VERSION 5.7 ;
  NOWIREEXTENSIONATPIN ON ;
  DIVIDERCHAR "/" ;
  BUSBITCHARS "[]" ;
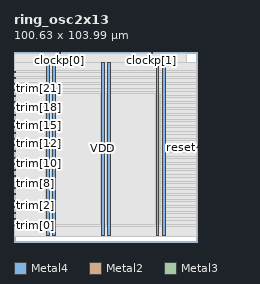
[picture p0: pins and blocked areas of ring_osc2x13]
MACRO ring_osc2x13
  CLASS BLOCK ;
  FOREIGN ring_osc2x13 ;
  ORIGIN 0.000 0.000 ;
  SIZE 100.630 BY 103.990 ;
  PIN VDD
    DIRECTION INOUT ;
    USE POWER ;
    PORT
      LAYER Metal4 ;
        RECT 17.760 3.620 19.360 98.300 ;
    END
    PORT
      LAYER Metal4 ;
        RECT 47.760 3.620 49.360 98.300 ;
    END
    PORT
      LAYER Metal4 ;
        RECT 77.760 3.620 79.360 98.300 ;
    END
  END VDD
  PIN VSS
    DIRECTION INOUT ;
    USE GROUND ;
    PORT
      LAYER Metal4 ;
        RECT 21.060 3.620 22.660 98.300 ;
    END
    PORT
      LAYER Metal4 ;
        RECT 51.060 3.620 52.660 98.300 ;
    END
    PORT
      LAYER Metal4 ;
        RECT 81.060 3.620 82.660 98.300 ;
    END
  END VSS
  PIN clockp[0]
    DIRECTION OUTPUT ;
    USE SIGNAL ;
    ANTENNADIFFAREA 4.024000 ;
    PORT
      LAYER Metal2 ;
        RECT 24.640 103.430 25.200 103.990 ;
    END
  END clockp[0]
  PIN clockp[1]
    DIRECTION OUTPUT ;
    USE SIGNAL ;
    ANTENNADIFFAREA 4.024000 ;
    PORT
      LAYER Metal2 ;
        RECT 75.040 103.430 75.600 103.990 ;
    END
  END clockp[1]
  PIN reset
    DIRECTION INPUT ;
    USE SIGNAL ;
    ANTENNAGATEAREA 3.848000 ;
    ANTENNADIFFAREA 1.231200 ;
    PORT
      LAYER Metal3 ;
        RECT 100.070 51.520 100.630 52.080 ;
    END
  END reset
  PIN trim[0]
    DIRECTION INPUT ;
    USE SIGNAL ;
    ANTENNAGATEAREA 0.552000 ;
    ANTENNADIFFAREA 0.410400 ;
    PORT
      LAYER Metal3 ;
        RECT 0.000 8.960 0.560 9.520 ;
    END
  END trim[0]
  PIN trim[10]
    DIRECTION INPUT ;
    USE SIGNAL ;
    ANTENNAGATEAREA 0.552000 ;
    ANTENNADIFFAREA 0.410400 ;
    PORT
      LAYER Metal3 ;
        RECT 0.000 42.560 0.560 43.120 ;
    END
  END trim[10]
  PIN trim[11]
    DIRECTION INPUT ;
    USE SIGNAL ;
    ANTENNAGATEAREA 0.552000 ;
    ANTENNADIFFAREA 0.410400 ;
    PORT
      LAYER Metal3 ;
        RECT 0.000 45.920 0.560 46.480 ;
    END
  END trim[11]
  PIN trim[12]
    DIRECTION INPUT ;
    USE SIGNAL ;
    ANTENNAGATEAREA 0.552000 ;
    ANTENNADIFFAREA 0.410400 ;
    PORT
      LAYER Metal3 ;
        RECT 0.000 49.280 0.560 49.840 ;
    END
  END trim[12]
  PIN trim[13]
    DIRECTION INPUT ;
    USE SIGNAL ;
    ANTENNAGATEAREA 0.552000 ;
    ANTENNADIFFAREA 0.410400 ;
    PORT
      LAYER Metal3 ;
        RECT 0.000 52.640 0.560 53.200 ;
    END
  END trim[13]
  PIN trim[14]
    DIRECTION INPUT ;
    USE SIGNAL ;
    ANTENNAGATEAREA 0.552000 ;
    ANTENNADIFFAREA 0.410400 ;
    PORT
      LAYER Metal3 ;
        RECT 0.000 56.000 0.560 56.560 ;
    END
  END trim[14]
  PIN trim[15]
    DIRECTION INPUT ;
    USE SIGNAL ;
    ANTENNAGATEAREA 0.552000 ;
    ANTENNADIFFAREA 0.410400 ;
    PORT
      LAYER Metal3 ;
        RECT 0.000 59.360 0.560 59.920 ;
    END
  END trim[15]
  PIN trim[16]
    DIRECTION INPUT ;
    USE SIGNAL ;
    ANTENNAGATEAREA 0.552000 ;
    ANTENNADIFFAREA 0.410400 ;
    PORT
      LAYER Metal3 ;
        RECT 0.000 62.720 0.560 63.280 ;
    END
  END trim[16]
  PIN trim[17]
    DIRECTION INPUT ;
    USE SIGNAL ;
    ANTENNAGATEAREA 0.552000 ;
    ANTENNADIFFAREA 0.410400 ;
    PORT
      LAYER Metal3 ;
        RECT 0.000 66.080 0.560 66.640 ;
    END
  END trim[17]
  PIN trim[18]
    DIRECTION INPUT ;
    USE SIGNAL ;
    ANTENNAGATEAREA 0.552000 ;
    ANTENNADIFFAREA 0.410400 ;
    PORT
      LAYER Metal3 ;
        RECT 0.000 69.440 0.560 70.000 ;
    END
  END trim[18]
  PIN trim[19]
    DIRECTION INPUT ;
    USE SIGNAL ;
    ANTENNAGATEAREA 0.552000 ;
    ANTENNADIFFAREA 0.410400 ;
    PORT
      LAYER Metal3 ;
        RECT 0.000 72.800 0.560 73.360 ;
    END
  END trim[19]
  PIN trim[1]
    DIRECTION INPUT ;
    USE SIGNAL ;
    ANTENNAGATEAREA 0.552000 ;
    ANTENNADIFFAREA 0.410400 ;
    PORT
      LAYER Metal3 ;
        RECT 0.000 12.320 0.560 12.880 ;
    END
  END trim[1]
  PIN trim[20]
    DIRECTION INPUT ;
    USE SIGNAL ;
    ANTENNAGATEAREA 0.552000 ;
    ANTENNADIFFAREA 0.410400 ;
    PORT
      LAYER Metal3 ;
        RECT 0.000 76.160 0.560 76.720 ;
    END
  END trim[20]
  PIN trim[21]
    DIRECTION INPUT ;
    USE SIGNAL ;
    ANTENNAGATEAREA 0.552000 ;
    ANTENNADIFFAREA 0.410400 ;
    PORT
      LAYER Metal3 ;
        RECT 0.000 79.520 0.560 80.080 ;
    END
  END trim[21]
  PIN trim[22]
    DIRECTION INPUT ;
    USE SIGNAL ;
    ANTENNAGATEAREA 0.552000 ;
    ANTENNADIFFAREA 0.410400 ;
    PORT
      LAYER Metal3 ;
        RECT 0.000 82.880 0.560 83.440 ;
    END
  END trim[22]
  PIN trim[23]
    DIRECTION INPUT ;
    USE SIGNAL ;
    ANTENNAGATEAREA 0.552000 ;
    ANTENNADIFFAREA 0.410400 ;
    PORT
      LAYER Metal3 ;
        RECT 0.000 86.240 0.560 86.800 ;
    END
  END trim[23]
  PIN trim[24]
    DIRECTION INPUT ;
    USE SIGNAL ;
    ANTENNAGATEAREA 0.552000 ;
    ANTENNADIFFAREA 0.410400 ;
    PORT
      LAYER Metal3 ;
        RECT 0.000 89.600 0.560 90.160 ;
    END
  END trim[24]
  PIN trim[25]
    DIRECTION INPUT ;
    USE SIGNAL ;
    ANTENNAGATEAREA 0.552000 ;
    ANTENNADIFFAREA 0.410400 ;
    PORT
      LAYER Metal3 ;
        RECT 0.000 92.960 0.560 93.520 ;
    END
  END trim[25]
  PIN trim[2]
    DIRECTION INPUT ;
    USE SIGNAL ;
    ANTENNAGATEAREA 0.552000 ;
    ANTENNADIFFAREA 0.410400 ;
    PORT
      LAYER Metal3 ;
        RECT 0.000 15.680 0.560 16.240 ;
    END
  END trim[2]
  PIN trim[3]
    DIRECTION INPUT ;
    USE SIGNAL ;
    ANTENNAGATEAREA 0.552000 ;
    ANTENNADIFFAREA 0.410400 ;
    PORT
      LAYER Metal3 ;
        RECT 0.000 19.040 0.560 19.600 ;
    END
  END trim[3]
  PIN trim[4]
    DIRECTION INPUT ;
    USE SIGNAL ;
    ANTENNAGATEAREA 0.552000 ;
    ANTENNADIFFAREA 0.410400 ;
    PORT
      LAYER Metal3 ;
        RECT 0.000 22.400 0.560 22.960 ;
    END
  END trim[4]
  PIN trim[5]
    DIRECTION INPUT ;
    USE SIGNAL ;
    ANTENNAGATEAREA 0.552000 ;
    ANTENNADIFFAREA 0.410400 ;
    PORT
      LAYER Metal3 ;
        RECT 0.000 25.760 0.560 26.320 ;
    END
  END trim[5]
  PIN trim[6]
    DIRECTION INPUT ;
    USE SIGNAL ;
    ANTENNAGATEAREA 0.552000 ;
    ANTENNADIFFAREA 0.410400 ;
    PORT
      LAYER Metal3 ;
        RECT 0.000 29.120 0.560 29.680 ;
    END
  END trim[6]
  PIN trim[7]
    DIRECTION INPUT ;
    USE SIGNAL ;
    ANTENNAGATEAREA 0.552000 ;
    ANTENNADIFFAREA 0.410400 ;
    PORT
      LAYER Metal3 ;
        RECT 0.000 32.480 0.560 33.040 ;
    END
  END trim[7]
  PIN trim[8]
    DIRECTION INPUT ;
    USE SIGNAL ;
    ANTENNAGATEAREA 0.552000 ;
    ANTENNADIFFAREA 0.410400 ;
    PORT
      LAYER Metal3 ;
        RECT 0.000 35.840 0.560 36.400 ;
    END
  END trim[8]
  PIN trim[9]
    DIRECTION INPUT ;
    USE SIGNAL ;
    ANTENNAGATEAREA 0.552000 ;
    ANTENNADIFFAREA 0.410400 ;
    PORT
      LAYER Metal3 ;
        RECT 0.000 39.200 0.560 39.760 ;
    END
  END trim[9]
  OBS
      LAYER Nwell ;
        RECT 1.810 3.490 98.430 98.430 ;
      LAYER Metal1 ;
        RECT 2.240 3.620 98.000 98.300 ;
      LAYER Metal2 ;
        RECT 0.140 103.130 24.340 103.430 ;
        RECT 25.500 103.130 74.740 103.430 ;
        RECT 75.900 103.130 94.500 103.430 ;
        RECT 0.140 2.890 94.500 103.130 ;
      LAYER Metal3 ;
        RECT 0.090 93.820 100.070 98.140 ;
        RECT 0.860 92.660 100.070 93.820 ;
        RECT 0.090 90.460 100.070 92.660 ;
        RECT 0.860 89.300 100.070 90.460 ;
        RECT 0.090 87.100 100.070 89.300 ;
        RECT 0.860 85.940 100.070 87.100 ;
        RECT 0.090 83.740 100.070 85.940 ;
        RECT 0.860 82.580 100.070 83.740 ;
        RECT 0.090 80.380 100.070 82.580 ;
        RECT 0.860 79.220 100.070 80.380 ;
        RECT 0.090 77.020 100.070 79.220 ;
        RECT 0.860 75.860 100.070 77.020 ;
        RECT 0.090 73.660 100.070 75.860 ;
        RECT 0.860 72.500 100.070 73.660 ;
        RECT 0.090 70.300 100.070 72.500 ;
        RECT 0.860 69.140 100.070 70.300 ;
        RECT 0.090 66.940 100.070 69.140 ;
        RECT 0.860 65.780 100.070 66.940 ;
        RECT 0.090 63.580 100.070 65.780 ;
        RECT 0.860 62.420 100.070 63.580 ;
        RECT 0.090 60.220 100.070 62.420 ;
        RECT 0.860 59.060 100.070 60.220 ;
        RECT 0.090 56.860 100.070 59.060 ;
        RECT 0.860 55.700 100.070 56.860 ;
        RECT 0.090 53.500 100.070 55.700 ;
        RECT 0.860 52.380 100.070 53.500 ;
        RECT 0.860 52.340 99.770 52.380 ;
        RECT 0.090 51.220 99.770 52.340 ;
        RECT 0.090 50.140 100.070 51.220 ;
        RECT 0.860 48.980 100.070 50.140 ;
        RECT 0.090 46.780 100.070 48.980 ;
        RECT 0.860 45.620 100.070 46.780 ;
        RECT 0.090 43.420 100.070 45.620 ;
        RECT 0.860 42.260 100.070 43.420 ;
        RECT 0.090 40.060 100.070 42.260 ;
        RECT 0.860 38.900 100.070 40.060 ;
        RECT 0.090 36.700 100.070 38.900 ;
        RECT 0.860 35.540 100.070 36.700 ;
        RECT 0.090 33.340 100.070 35.540 ;
        RECT 0.860 32.180 100.070 33.340 ;
        RECT 0.090 29.980 100.070 32.180 ;
        RECT 0.860 28.820 100.070 29.980 ;
        RECT 0.090 26.620 100.070 28.820 ;
        RECT 0.860 25.460 100.070 26.620 ;
        RECT 0.090 23.260 100.070 25.460 ;
        RECT 0.860 22.100 100.070 23.260 ;
        RECT 0.090 19.900 100.070 22.100 ;
        RECT 0.860 18.740 100.070 19.900 ;
        RECT 0.090 16.540 100.070 18.740 ;
        RECT 0.860 15.380 100.070 16.540 ;
        RECT 0.090 13.180 100.070 15.380 ;
        RECT 0.860 12.020 100.070 13.180 ;
        RECT 0.090 9.820 100.070 12.020 ;
        RECT 0.860 8.660 100.070 9.820 ;
        RECT 0.090 2.940 100.070 8.660 ;
      LAYER Metal4 ;
        RECT 0.700 9.610 17.460 81.110 ;
        RECT 19.660 9.610 20.760 81.110 ;
        RECT 22.960 9.610 47.460 81.110 ;
        RECT 49.660 9.610 50.760 81.110 ;
        RECT 52.960 9.610 77.460 81.110 ;
        RECT 79.660 9.610 79.940 81.110 ;
  END
END ring_osc2x13
END LIBRARY

